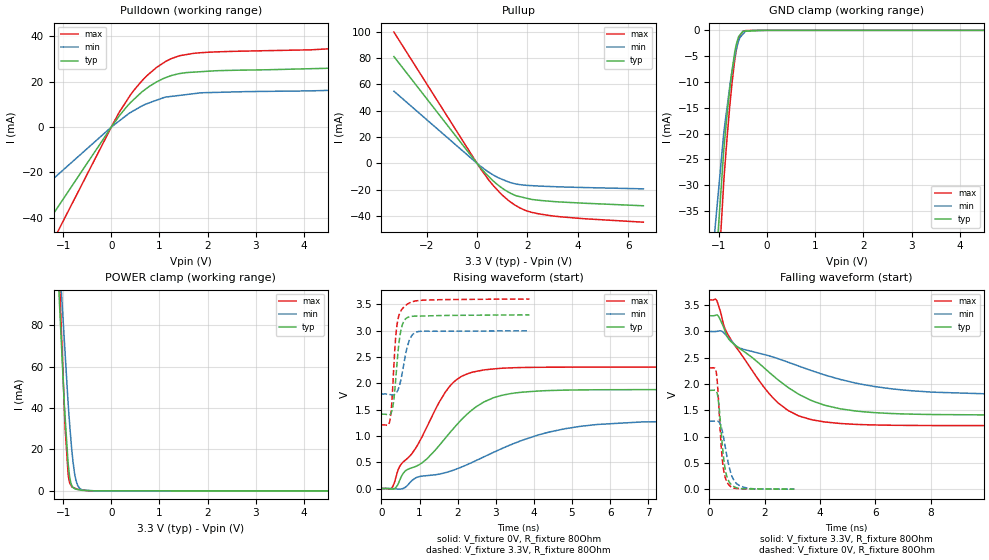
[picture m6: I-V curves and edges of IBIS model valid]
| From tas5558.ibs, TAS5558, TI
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|   valid Model
[Model]   valid
Model_type   3-state
Polarity   Non-Inverting
Vmeas = 1.65
Vref = 1.65
Cref = 2pF
Rref = 80
|   typ   min   max
|   (nom PVT)   (fast PVT)   (slow PVT)
|C_comp from frequency sweep method (F=50MHz)
|C_comp   3.070e-12   2.898e-12   3.263e-12
|ON state : BUFFER OUTPUT TURNED HIGH
|C_comp   3.070e-12   2.898e-12   3.263e-12
|OFF state: BUFFER IN HIGH IMPEDANCE
|C_comp   1.440e-12   1.437e-12   1.448e-12
|C_comp from LC tank measurement(L=1nH)
|Resonant Frequency(Hz)   4.410e+09   4.450e+09   4.380e+09
C_comp   1.304e-12   1.280e-12   1.322e-12
|ON state : BUFFER OUTPUT TURNED HIGH
|Resonant Frequency(Hz)   4.410e+09   4.450e+09   4.380e+09
|C_comp   1.304e-12   1.280e-12   1.322e-12
|OFF state: BUFFER IN HIGH IMPEDANCE
|Resonant Frequency(Hz)   4.580e+09   4.640e+09   4.530e+09
|C_comp   1.209e-12   1.178e-12   1.236e-12
| Where nom  PVT is Nominal Process, 3.3V, 27C
|   Fast PVT is Strong Process,  3.6V, 0C
|   Slow PVT is Weak Process,   3V, 125C
[Voltage Range]   3.3   3   3.6
|Ambient Temperature   27   125   0
|Junction Temperature
[Temperature Range]   27   125   0
[Pullup Reference]   3.3   3   3.6
[Pulldown Reference]   0   0   0
[Power Clamp Reference]   3.3   3   3.6
[GND Clamp Reference]   0   0   0
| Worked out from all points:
|   slope of the pulldown table from 0 to 0.495 V, typ, clamps not added: 38.8 ohm
|   slope of the pullup table from 0 to 0.495 V, typ, clamps not added: 46.9 ohm
|   GND clamp passes 1 mA (typ) near -0.57 V on its own axis
|   POWER clamp passes 1 mA (typ) near -0.75 V on its own axis
|   falling waveform, V_fixture 3.3V, R_fixture 80Ohm: 20-80 % time 2.66ns typ, 4.23ns min, 1.88ns max; typ from 3.3 V to 1.41 V
|   rising waveform, V_fixture 0V, R_fixture 80Ohm: 20-80 % time 1.67ns typ, 2.82ns min, 1.17ns max; typ from 0 V to 1.88 V
|   rising waveform, V_fixture 3.3V, R_fixture 80Ohm: 20-80 % time 150ps typ, 205ps min, 135ps max; typ from 1.41 V to 3.3 V
|   falling waveform, V_fixture 0V, R_fixture 80Ohm: 20-80 % time 212ps typ, 311ps min, 177ps max; typ from 1.88 V to 0.002 V
[Pulldown]
|   Voltage   I(typ)   I(min)   I(max)
-3.3V     -104.8mA   -62.36mA   -136.8mA
-132mV    -4.193mA   -2.494mA   -5.472mA
172.8mV   5.184mA    2.866mA    6.814mA
478.8mV   12.43mA    7.439mA    16.49mA
939.6mV   19.95mA    11.89mA    26.32mA
1.246V    22.75mA    13.56mA    30.23mA
1.829V    24.43mA    15.06mA    32.79mA
4.162V    25.79mA    16.03mA    34.12mA
5.174V    27.87mA    17.42mA    36.98mA
5.726V    31.62mA    19.38mA    41.9mA
6V        34.91mA    21.05mA    46.09mA
6.6V      44.69mA    24.71mA    58.92mA
[GND Clamp]
|   Voltage   I(typ)   I(min)   I(max)
-3.3V     -1.71A     -1.468A    -1.81A
-1.544V   -110.1mA   -85.34mA   -132.2mA
-897.6mV  -22.81mA   -19.58mA   -28.83mA
-818.4mV  -14.96mA   -13.9mA    -19.31mA
-781.2mV  -11.85mA   -11.24mA   -15.21mA
-745.8mV  -8.881mA   -8.983mA   -11.8mA
-680.4mV  -4.702mA   -5.456mA   -6.295mA
-633.6mV  -2.471mA   -3.457mA   -3.447mA
-594mV    -1.271mA   -2.112mA   -1.8mA
-501.6mV  -167.9uA   -727.6uA   -252.5uA
-285mV    -94.91uA   -5.727uA   -22.97uA
6.6V      0A         0A         0A
[Pullup]
|   Voltage   I(typ)   I(min)   I(max)
-3.3V     80.99mA    54.74mA    99.56mA
172.8mV   -4.03mA    -2.652mA   -5.005mA
633.6mV   -13.2mA    -8.722mA   -16.61mA
939.6mV   -18.01mA   -11.65mA   -22.92mA
1.278V    -22.12mA   -14.3mA    -28.6mA
1.554V    -24.58mA   -15.65mA   -32.17mA
1.912V    -26.18mA   -16.57mA   -35.59mA
2.473V    -28mA      -17.19mA   -38.35mA
4.162V    -30.11mA   -18.27mA   -41.84mA
6.6V      -32.14mA   -19.3mA    -44.59mA
[POWER Clamp]
|   Voltage   I(typ)   I(min)   I(max)
-3.3V     1.403A     1.109A     1.949A
-1.082V   93.4mA     113.8mA    109.3mA
-1.051V   78.23mA    101.8mA    86.31mA
-1.048V   76.49mA    100.4mA    83.84mA
-961.2mV  36.3mA     67.1mA     30.99mA
-896.4mV  13.23mA    42.16mA    8.051mA
-838.2mV  3.759mA    24.54mA    2.772mA
-795mV    1.728mA    14.02mA    1.674mA
-745.8mV  919.8uA    6.439mA    1.224mA
-660mV    458uA      1.301mA    674uA
-330mV    36.26uA    24.12uA    66.11uA
6.6V      0A         0A         0A
[Ramp]
R_load = 80
|   typ   min   max
dV/dt_r   1.12741/1.66751e-09   0.775387/2.81302e-09   1.38319/1.17257e-09
dV/dt_f   1.13316/2.66456e-09   0.723177/4.24401e-09   1.4338/1.87458e-09
[Falling Waveform]
V_fixture = 3.3V
V_fixture_min = 3V
V_fixture_max = 3.6V
R_fixture = 80Ohm
|   Time   V(typ)   V(min)   V(max)
0s        3.299V     2.999V     3.599V
252ps     3.312V     3V         3.602V
644ps     2.903V     2.905V     2.966V
1.1ns     2.672V     2.683V     2.604V
1.96ns    2.317V     2.564V     1.949V
2.492ns   2.076V     2.481V     1.638V
3.288ns   1.789V     2.331V     1.385V
4.712ns   1.532V     2.091V     1.251V
6.852ns   1.434V     1.894V     1.215V
13.35ns   1.411V     1.797V     1.209V
[Rising Waveform]
V_fixture = 0V
V_fixture_min = 0V
V_fixture_max = 0V
R_fixture = 80Ohm
|   Time   V(typ)   V(min)   V(max)
0s        1.665nV    35.52nV    1.383nV
288ps     -12.02mV   231.1uV    28.12mV
484ps     166.5mV    -11.79mV   426.1mV
640ps     341.6mV    30.31mV    546.6mV
896ps     418.7mV    201.4mV    764.3mV
1.796ns   1.061V     326.7mV    1.946V
2.476ns   1.548V     528.9mV    2.223V
3.496ns   1.814V     861.6mV    2.295V
5.672ns   1.876V     1.217V     2.305V
15ns      1.879V     1.292V     2.305V
[Rising Waveform]
V_fixture = 3.3V
V_fixture_min = 3V
V_fixture_max = 3.6V
R_fixture = 80Ohm
|   Time   V(typ)   V(min)   V(max)
0s        1.41V      1.794V     1.209V
200ps     1.397V     1.788V     1.236V
276ps     1.478V     1.778V     1.679V
356ps     1.914V     1.793V     2.701V
408ps     2.372V     1.837V     3.104V
504ps     2.978V     2.045V     3.364V
636ps     3.224V     2.558V     3.478V
784ps     3.269V     2.89V      3.541V
996ps     3.275V     2.985V     3.572V
3.884ns   3.298V     2.995V     3.598V
[Falling Waveform]
V_fixture = 0V
V_fixture_min = 0V
V_fixture_max = 0V
R_fixture = 80Ohm
|   Time   V(typ)   V(min)   V(max)
0s        1.879V     1.292V     2.305V
244ps     1.869V     1.3V       2.238V
336ps     1.643V     1.282V     1.643V
412ps     1.195V     1.213V     944.8mV
472ps     819.5mV    1.096V     546.6mV
572ps     382.8mV    811.3mV    228mV
668ps     191.8mV    539.5mV    108.8mV
840ps     66.58mV    217mV      30.64mV
1.096ns   13.8mV     68.23mV    10.45mV
3.068ns   1.874mV    2.621mV    1.307mV
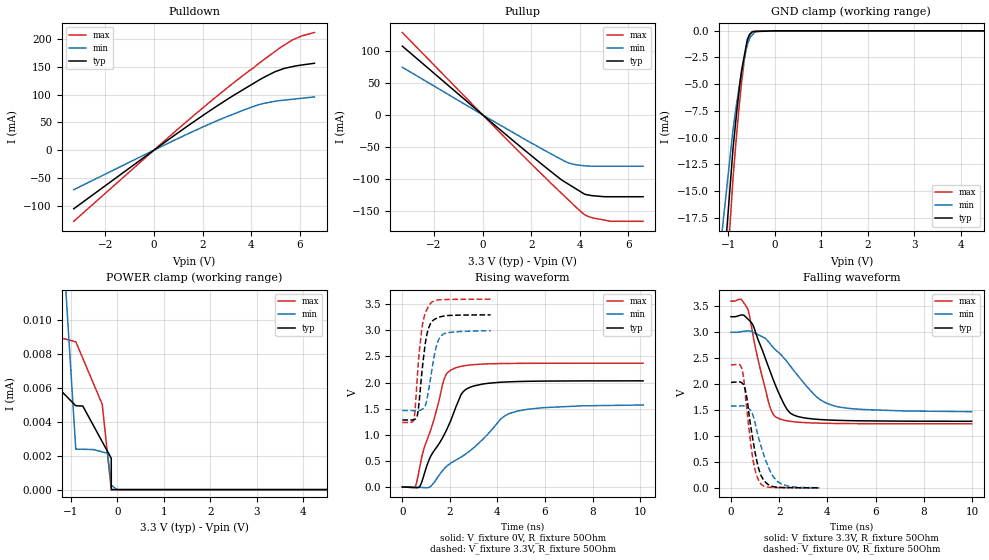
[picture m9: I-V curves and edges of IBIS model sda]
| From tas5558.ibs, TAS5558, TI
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|   sda Model
[Model]   sda
Model_type   I/O
Polarity   Non-Inverting
Enable   Active-Low
Vinl = 0.8
Vinh = 2.0
Vmeas = 1.65
Vref = 1.65
Cref = 400pF
Rref = 50
|   typ   min   max
|   (nom PVT)   (fast PVT)   (slow PVT)
|C_comp from frequency sweep method (F=400KHz)
|Average
C_comp   3.757e-12   3.627e-12   3.916e-12
|ON state : BUFFER OUTPUT TURNED HIGH
|C_comp   2.151e-12   2.001e-12   2.354e-12
|OFF state: BUFFER IN HIGH IMPEDANCE
|C_comp   5.364e-12   5.254e-12   5.478e-12
|C_comp from LC tank measurement(L=1nH)
|Average
|Resonant Frequency(Hz)   4.305e+09   4.925e+09   4.045e+09
|C_comp   1.457e-12   1.055e-12   1.774e-12
|ON state : BUFFER OUTPUT TURNED HIGH
|Resonant Frequency(Hz)   4.930e+09   5.190e+09   4.900e+09
|C_comp   1.043e-12   9.413e-13   1.056e-12
|OFF state: BUFFER IN HIGH IMPEDANCE
|Resonant Frequency(Hz)   3.680e+09   4.660e+09   3.190e+09
|C_comp   1.872e-12   1.168e-12   2.492e-12
| Where nom  PVT is Nominal Process, 3.3V, 27C
|   Fast PVT is Strong Process,  3.6V, 0C
|   Slow PVT is Weak Process,   3V, 125C
[Voltage Range]   3.3   3   3.6
|Ambient Temperature   27   125   0
|Junction Temperature
[Temperature Range]   27   125   0
[Pullup Reference]   3.3   3   3.6
[Pulldown Reference]   0   0   0
[Power Clamp Reference]   3.3   3   3.6
[GND Clamp Reference]   0   0   0
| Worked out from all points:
|   slope of the pulldown table from 0 to 0.495 V, typ, clamps not added: 31.5 ohm
|   slope of the pullup table from 0 to 0.495 V, typ, clamps not added: 30.9 ohm
|   GND clamp passes 1 mA (typ) near -0.60 V on its own axis
|   POWER clamp passes 1 mA (typ) near -3.28 V on its own axis
|   falling waveform, V_fixture 3.3V, R_fixture 50Ohm: 20-80 % time 1.03ns typ, 1.73ns min, 685ps max; typ from 3.3 V to 1.28 V
|   rising waveform, V_fixture 0V, R_fixture 50Ohm: 20-80 % time 1.31ns typ, 2.36ns min, 885ps max; typ from 0 V to 2.03 V
|   rising waveform, V_fixture 3.3V, R_fixture 50Ohm: 20-80 % time 302ps typ, 356ps min, 282ps max; typ from 1.28 V to 3.3 V
|   falling waveform, V_fixture 0V, R_fixture 50Ohm: 20-80 % time 436ps typ, 636ps min, 363ps max; typ from 2.03 V to 0.001 V
[Pulldown]
|   Voltage   I(typ)   I(min)   I(max)
-3.3V     -105.6mA   -71.18mA   -128.1mA
940.5mV   29.71mA    19.9mA     36.13mA
2.286V    70.52mA    47.05mA    86.18mA
3.241V    97.66mA    64.37mA    120mA
4.314V    125.9mA    81.76mA    156mA
4.97V     141mA      87.84mA    177.3mA
5.356V    147.1mA    90.02mA    189mA
5.699V    150.3mA    91.6mA     198.4mA
6.095V    153.3mA    93.42mA    205.9mA
6.6V      156.4mA    95.75mA    211.6mA
[GND Clamp]
|   Voltage   I(typ)   I(min)   I(max)
-3.3V     -1.925A    -1.647A    -2.036A
-1.58V    -49.88mA   -36.99mA   -59.97mA
-897.6mV  -11.07mA   -9.273mA   -13.86mA
-828mV    -8.039mA   -7.078mA   -10.13mA
-745.8mV  -4.828mA   -4.744mA   -6.251mA
-712.8mV  -3.716mA   -3.966mA   -4.841mA
-662.4mV  -2.532mA   -2.779mA   -3.012mA
-576mV    -685uA     -1.143mA   -892uA
-481.8mV  -81.36uA   -384.5uA   -111.8uA
-420mV    -70.85uA   -82.75uA   -28.91uA
-285mV    -47.9uA    -3.54uA    -15.3uA
6.6V      0A         0A         0A
[Pullup]
|   Voltage   I(typ)   I(min)   I(max)
-3.3V     107.2mA    74.22mA    128.4mA
785.4mV   -25.33mA   -17.46mA   -30.38mA
2.781V    -87.67mA   -60.33mA   -105.7mA
3.241V    -101.5mA   -69.68mA   -122.5mA
3.549V    -108.8mA   -75.37mA   -133.6mA
4.162V    -123.2mA   -79.38mA   -155.1mA
4.504V    -126.2mA   -80.24mA   -160.8mA
5.267V    -127.9mA   -80.24mA   -166.3mA
6.6V      -127.9mA   -80.24mA   -166.3mA
[POWER Clamp]
|   Voltage   I(typ)   I(min)   I(max)
-3.3V     1.043mA    5.986mA    1.052mA
-2.262V   46.15uA    205.9uA    34.83uA
-2.059V   8.187uA    121.1uA    9.526uA
-1.878V   7.681uA    45.37uA    9.4uA
-896.4mV  4.943uA    2.387uA    8.718uA
-745.8mV  4.928uA    2.377uA    7.741uA
-327.6mV  2.825uA    2.227uA    5.029uA
-213mV    2.249uA    2.147uA    2.067uA
-133.2mV  1.847uA    282.3nA    0A
-132mV    0A         254.3nA    0A
-3.3mV    0A         0A         0A
6.6V      0A         0A         0A
[Ramp]
R_load = 50
|   typ   min   max
dV/dt_r   1.21992/1.3052e-09   0.945179/2.36465e-09   1.42217/8.85621e-10
dV/dt_f   1.20989/1.03108e-09   0.921583/1.73886e-09   1.4187/6.84723e-10
[Falling Waveform]
V_fixture = 3.3V
V_fixture_min = 3V
V_fixture_max = 3.6V
R_fixture = 50Ohm
|   Time   V(typ)   V(min)   V(max)
0s        3.3V       3V         3.6V
416ps     3.332V     3.01V      3.637V
704ps     3.254V     3.026V     3.436V
940ps     3.109V     2.994V     2.875V
1.556ns   2.332V     2.817V     1.655V
1.884ns   1.934V     2.645V     1.359V
2.464ns   1.439V     2.348V     1.282V
3.468ns   1.326V     1.791V     1.25V
4.196ns   1.306V     1.593V     1.243V
9.988ns   1.284V     1.469V     1.236V
[Rising Waveform]
V_fixture = 0V
V_fixture_min = 0V
V_fixture_max = 0V
R_fixture = 50Ohm
|   Time   V(typ)   V(min)   V(max)
0s        962.7pV    58.26nV    722.2pV
560ps     -13.86mV   -2.555mV   25.69mV
780ps     52.81mV    -9.282mV   496.8mV
1.156ns   554.8mV    -1.119mV   1.045V
1.752ns   994.6mV    345.3mV    2.059V
2.052ns   1.29V      461.6mV    2.243V
2.468ns   1.769V     573mV      2.311V
2.664ns   1.867V     632.1mV    2.326V
4.496ns   2.015V     1.407V     2.367V
10.12ns   2.033V     1.57V      2.37V
[Rising Waveform]
V_fixture = 3.3V
V_fixture_min = 3V
V_fixture_max = 3.6V
R_fixture = 50Ohm
|   Time   V(typ)   V(min)   V(max)
0s        1.283V     1.463V     1.236V
480ps     1.288V     1.463V     1.295V
616ps     1.347V     1.463V     2.02V
704ps     1.623V     1.468V     2.55V
856ps     2.343V     1.493V     3.133V
1.004ns   2.86V      1.616V     3.373V
1.176ns   3.123V     2.062V     3.512V
1.404ns   3.224V     2.648V     3.575V
1.62ns    3.263V     2.892V     3.587V
3.712ns   3.297V     2.994V     3.599V
[Falling Waveform]
V_fixture = 0V
V_fixture_min = 0V
V_fixture_max = 0V
R_fixture = 50Ohm
|   Time   V(typ)   V(min)   V(max)
0s        2.033V     1.576V     2.37V
332ps     2.044V     1.579V     2.382V
460ps     2.02V      1.582V     2.282V
540ps     1.969V     1.578V     2.056V
648ps     1.765V     1.561V     1.548V
920ps     899.1mV    1.384V     525.5mV
1.22ns    269mV      844.4mV    87.34mV
1.628ns   43.16mV    320.2mV    11.04mV
1.928ns   11.92mV    123.9mV    5.411mV
3.66ns    1.179mV    2.54mV     557.5uV
